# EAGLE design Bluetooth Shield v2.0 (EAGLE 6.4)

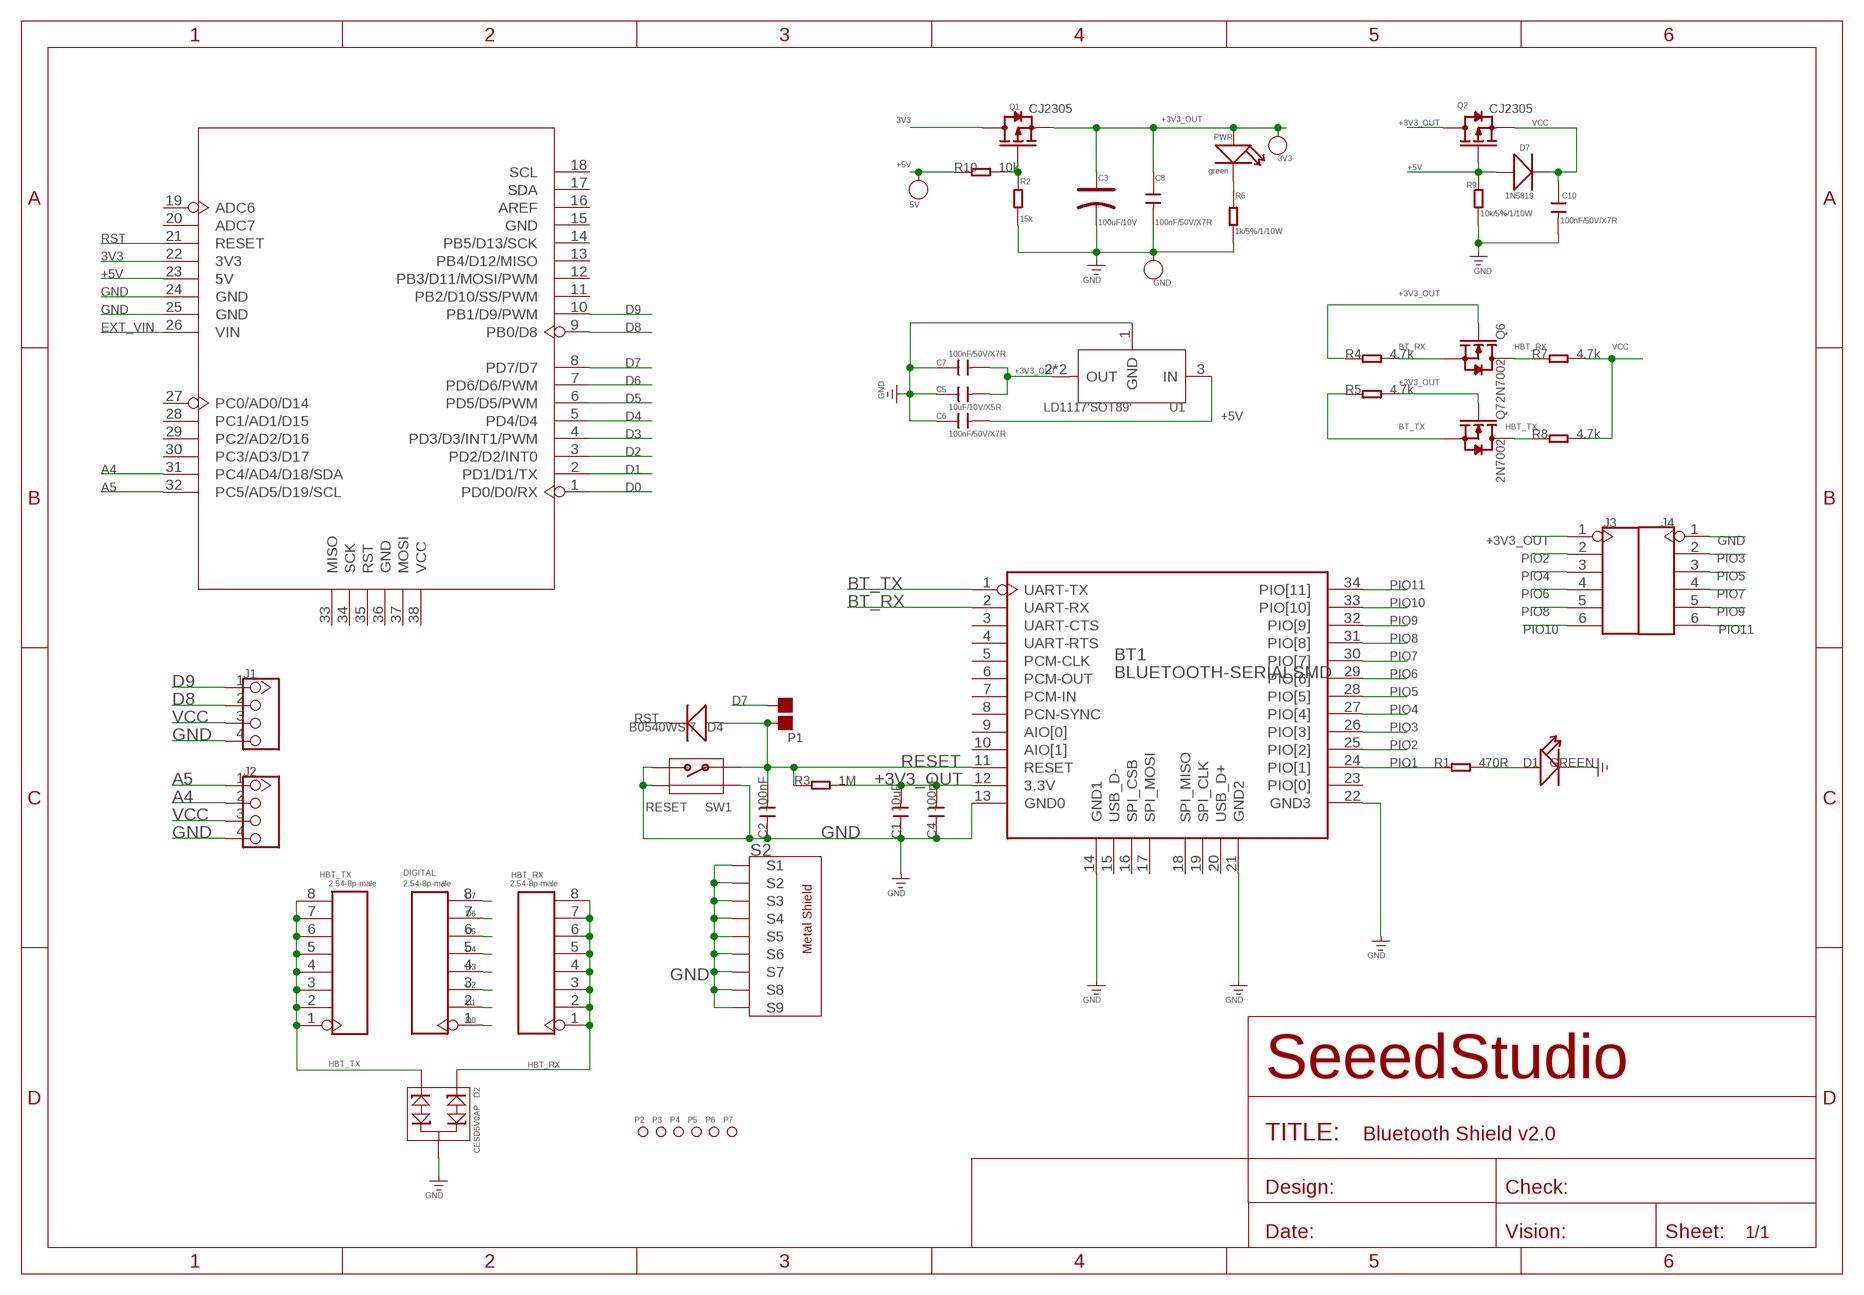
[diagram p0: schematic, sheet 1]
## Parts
3V3  PAD-TEST-POINT'4545'  [TP_4545]
5V  PAD-TEST-POINT'4545'  [TP_4545]
BT1  BLUETOOTH-SERIALSMD  [SERIAL_BLUETEETH]
C1  10uF  C-0805  [C0805]
C2  100nF  C-0603  [C0603]
C3  100uF/10V  CAP-AVX-B  [AVX-B]
C4  100nF  C-0603  [C0603]
C5  10uF/10V/X5R  C-0805  [C0805]
C6  100nF/50V/X7R  C-0603  [C0603]
C7  100nF/50V/X7R  C-0603  [C0603]
C8  100nF/50V/X7R  C-0603  [C0603]
C10  100nF/50V/X7R  C-0603  [C0603]
D1  GREEN  LED'0603'  [LED-0603]
D2  CESD5V0AP  D-ESD-PESDXL2BT  [SOT23]
D4  B0540WS-7  D'1206'  [SOD123]
D7  1N5819  D'DO-214AC'  [D2010]
DIGITAL  2.54-8p-male  HEADER-8P-2.54  [8P-2.54]
GND  GND  PAD-TEST-POINT'4545'  [TP_4545]
HBT_RX  2.54-8p-male  HEADER-8P-2.54  [8P-2.54]
HBT_TX  2.54-8p-male  HEADER-8P-2.54  [8P-2.54]
J1  TWIG-4P-2.0-2.0  [4P-2.0]
J2  TWIG-4P-2.0-2.0  [4P-2.0]
J3  HEADER-6P-65/35MIL  [6P-2.54-65/35MIL]
J4  HEADER-6P-65/35MIL  [6P-2.54-65/35MIL]
P1  PAD-JUMPER-2P  [2P-SMD-1.78X1.27]
P2  PAD-MARK'ANNULAR'  [ROUND-MARK-1.0]
P3  PAD-MARK'ANNULAR'  [ROUND-MARK-1.0]
P4  PAD-MARK'ANNULAR'  [ROUND-MARK-1.0]
P5  PAD-MARK'ANNULAR'  [ROUND-MARK-1.0]
P6  PAD-MARK'ANNULAR'  [ROUND-MARK-1.0]
P7  PAD-MARK'ANNULAR'  [ROUND-MARK-1.0]
PWR  green  LED'0603'  [LED-0603]
Q1  CJ2305  MOSFET-P'SI2323CDS/SI2305DS<BR>'  [SOT23]
Q2  CJ2305  MOSFET-P'SI2323CDS/SI2305DS<BR>'  [SOT23]
Q6  2N7002  MOSFET-N'SOT23'  [SOT23]
Q7  2N7002  MOSFET-N'SOT23'  [SOT23]
R1  470R  R-0603  [R0603]
R2  15k  R-0603  [R0603]
R3  1M  R-0603  [R0603]
R4  4.7k  R-0603  [R0603]
R5  4.7k  R-0603  [R0603]
R6  1k/5%/1/10W  R-0603  [R0603]
R7  4.7k  R-0603  [R0603]
R8  4.7k  R-0603  [R0603]
R9  10k/5%/1/10W  R-0603  [R0603]
R10  10k  R-0603  [R0603]
S2  EMI_SHIELD-FRAME_BT  [BT_SHIELD]
SW1  RESET  BUTTON-4P-REINFORCE'TS-1188E'  [4P-SMD-7X3.5X3.5H]
U1  LD1117'SOT89'  [SOT89]
U4  ARDUINO-38P'WITH/-SILK'  [ARDUINO-38P-WITH/-SILK-500519002]

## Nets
3V3: Q1.3(D) U4.22(3V3)
+3V3_OUT: 3V3.T BT1.12(3.3V) C1.2 C3.+ C4.2 C5.2 C7.2 C8.1 J3.1 PWR.+ Q1.2(S) Q2.3(D) Q6.1(G) Q7.1(G) R3.2 R4.1 R5.2 U1.2(OUT) U1.4(OUT)
+5V: 5V.T C6.2 D7.+ Q2.1(G) R9.1 R10.1 U1.3(IN) U4.23(5V)
A4: J2.2 U4.31(PC4/AD4/D18/SDA)
A5: J2.1 U4.32(PC5/AD5/D19/SCL)
BT_RX: BT1.2(UART-RX) Q6.2(S) R4.2
BT_TX: BT1.1(UART-TX) Q7.2(S) R5.1
D0: DIGITAL.1 U4.1(PD0/D0/RX)
D1: DIGITAL.2 U4.2(PD1/D1/TX)
D2: DIGITAL.3 U4.3(PD2/D2/INT0)
D3: DIGITAL.4 U4.4(PD3/D3/INT1/PWM)
D4: DIGITAL.5 U4.5(PD4/D4)
D5: DIGITAL.6 U4.6(PD5/D5/PWM)
D6: DIGITAL.7 U4.7(PD6/D6/PWM)
D7: DIGITAL.8 P1.1 U4.8(PD7/D7)
D8: J1.2 U4.9(PB0/D8)
D9: J1.1 U4.10(PB1/D9/PWM)
EXT_VIN: U4.26(VIN)
GND: BT1.13(GND0) BT1.14(GND1) BT1.21(GND2) BT1.22(GND3) C1.1 C2.1 C3.- C4.1 C5.1 C6.1 C7.1 C8.2 C10.2 D1.- D2.3 GND.T J1.4 J2.4 J4.1 R2.2 R6.1 R9.2 S2.S1 S2.S2 S2.S3 S2.S4 S2.S5 S2.S6 S2.S7 S2.S8 S2.S9 SW1.2 SW1.S1 SW1.S2 U1.1(GND) U4.24(GND) U4.25(GND)
HBT_RX: D2.1 HBT_RX.1 HBT_RX.2 HBT_RX.3 HBT_RX.4 HBT_RX.5 HBT_RX.6 HBT_RX.7 HBT_RX.8 Q6.3(D) R7.1
HBT_TX: D2.2 HBT_TX.1 HBT_TX.2 HBT_TX.3 HBT_TX.4 HBT_TX.5 HBT_TX.6 HBT_TX.7 HBT_TX.8 Q7.3(D) R8.1
N$1: Q1.1(G) R2.1 R10.2
N$5: D1.+ R1.2
N$26: PWR.- R6.2
PIO1: BT1.24(PIO[1]) R1.1
PIO2: BT1.25(PIO[2]) J3.2
PIO3: BT1.26(PIO[3]) J4.2
PIO4: BT1.27(PIO[4]) J3.3
PIO5: BT1.28(PIO[5]) J4.3
PIO6: BT1.29(PIO[6]) J3.4
PIO7: BT1.30(PIO[7]) J4.4
PIO8: BT1.31(PIO[8]) J3.5
PIO9: BT1.32(PIO[9]) J4.5
PIO10: BT1.33(PIO[10]) J3.6
PIO11: BT1.34(PIO[11]) J4.6
RESET: BT1.11(RESET) C2.2 D4.+ P1.2 R3.1 SW1.1
RST: D4.- U4.21(RESET)
VCC: C10.1 D7.- J1.3 J2.3 Q2.2(S) R7.2 R8.2
Unconnected: BT1.3(UART-CTS) BT1.4(UART-RTS) BT1.5(PCM-CLK) BT1.6(PCM-OUT) BT1.7(PCM-IN) BT1.8(PCN-SYNC) BT1.9(AIO[0]) BT1.10(AIO[1]) BT1.15(USB_D-) BT1.16(SPI_CSB) BT1.17(SPI_MOSI) BT1.18(SPI_MISO) BT1.19(SPI_CLK) BT1.20(USB_D+) BT1.23(PIO[0]) U4.11(PB2/D10/SS/PWM) U4.12(PB3/D11/MOSI/PWM) U4.13(PB4/D12/MISO) U4.14(PB5/D13/SCK) U4.15(GND) U4.16(AREF) U4.17(SDA) U4.18(SCL) U4.19(ADC6) U4.20(ADC7) U4.27(PC0/AD0/D14) U4.28(PC1/AD1/D15) U4.29(PC2/AD2/D16) U4.30(PC3/AD3/D17) U4.33(MISO) U4.34(SCK) U4.35(RST) U4.36(GND) U4.37(MOSI) U4.38(VCC)

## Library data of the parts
3V3 5V GND = Discrete:PAD-TEST-POINT; PARTNO: DNP
BT1 = Module:BLUETOOTH-SERIAL
C1 C2 C4-C8 C10 = Discrete:C*: Ceramic Capacitors
C3 = Discrete:CAP*: Electrolytic Capacitors,Tantalum Capacitors and Super Capacitors
D1 PWR = Discrete:LED*
D2 = Discrete:D-ESD-PESDXL2BT
D4 D7 = Discrete:D*
DIGITAL HBT_RX HBT_TX = Connector:HEADER-8P
J1 J2 = Connector :TWIG-4P-2.0
J3 J4 = Connector :HEADER-6P
P1 = Discrete:PAD-JUMPER-2P; PARTNO: DNP
P2-P7 = Discrete:PAD-MARK; PARTNO: DNP
Q1 Q2 = Discrete:MOSFET-P
Q6 Q7 = Discrete:MOSFET-N: IRLL014: http://www.vishay.com/docs/91319/sihll014.pdf
R1-R10 = Discrete:R*
S2 = moudle:EMI_SHIELD-FRAME
SW1 = Discrete:BUTTON-4P-REINFORCE: TS-1188E http://www.best-dz.com/?thread-374-2.html
U1 = IC:LD1117: Low Drop Fixed And Adjustable Positive Voltage Regulators http://www.datasheetcatalog.org/datasheet/SGSThomsonMicroelectronics/mXuqtqv.pdf
U4 = moudle:ARDUINO-38P

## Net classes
0 default: width 0.003 mm, drill 0.254 mm, clearance 0.152 mm

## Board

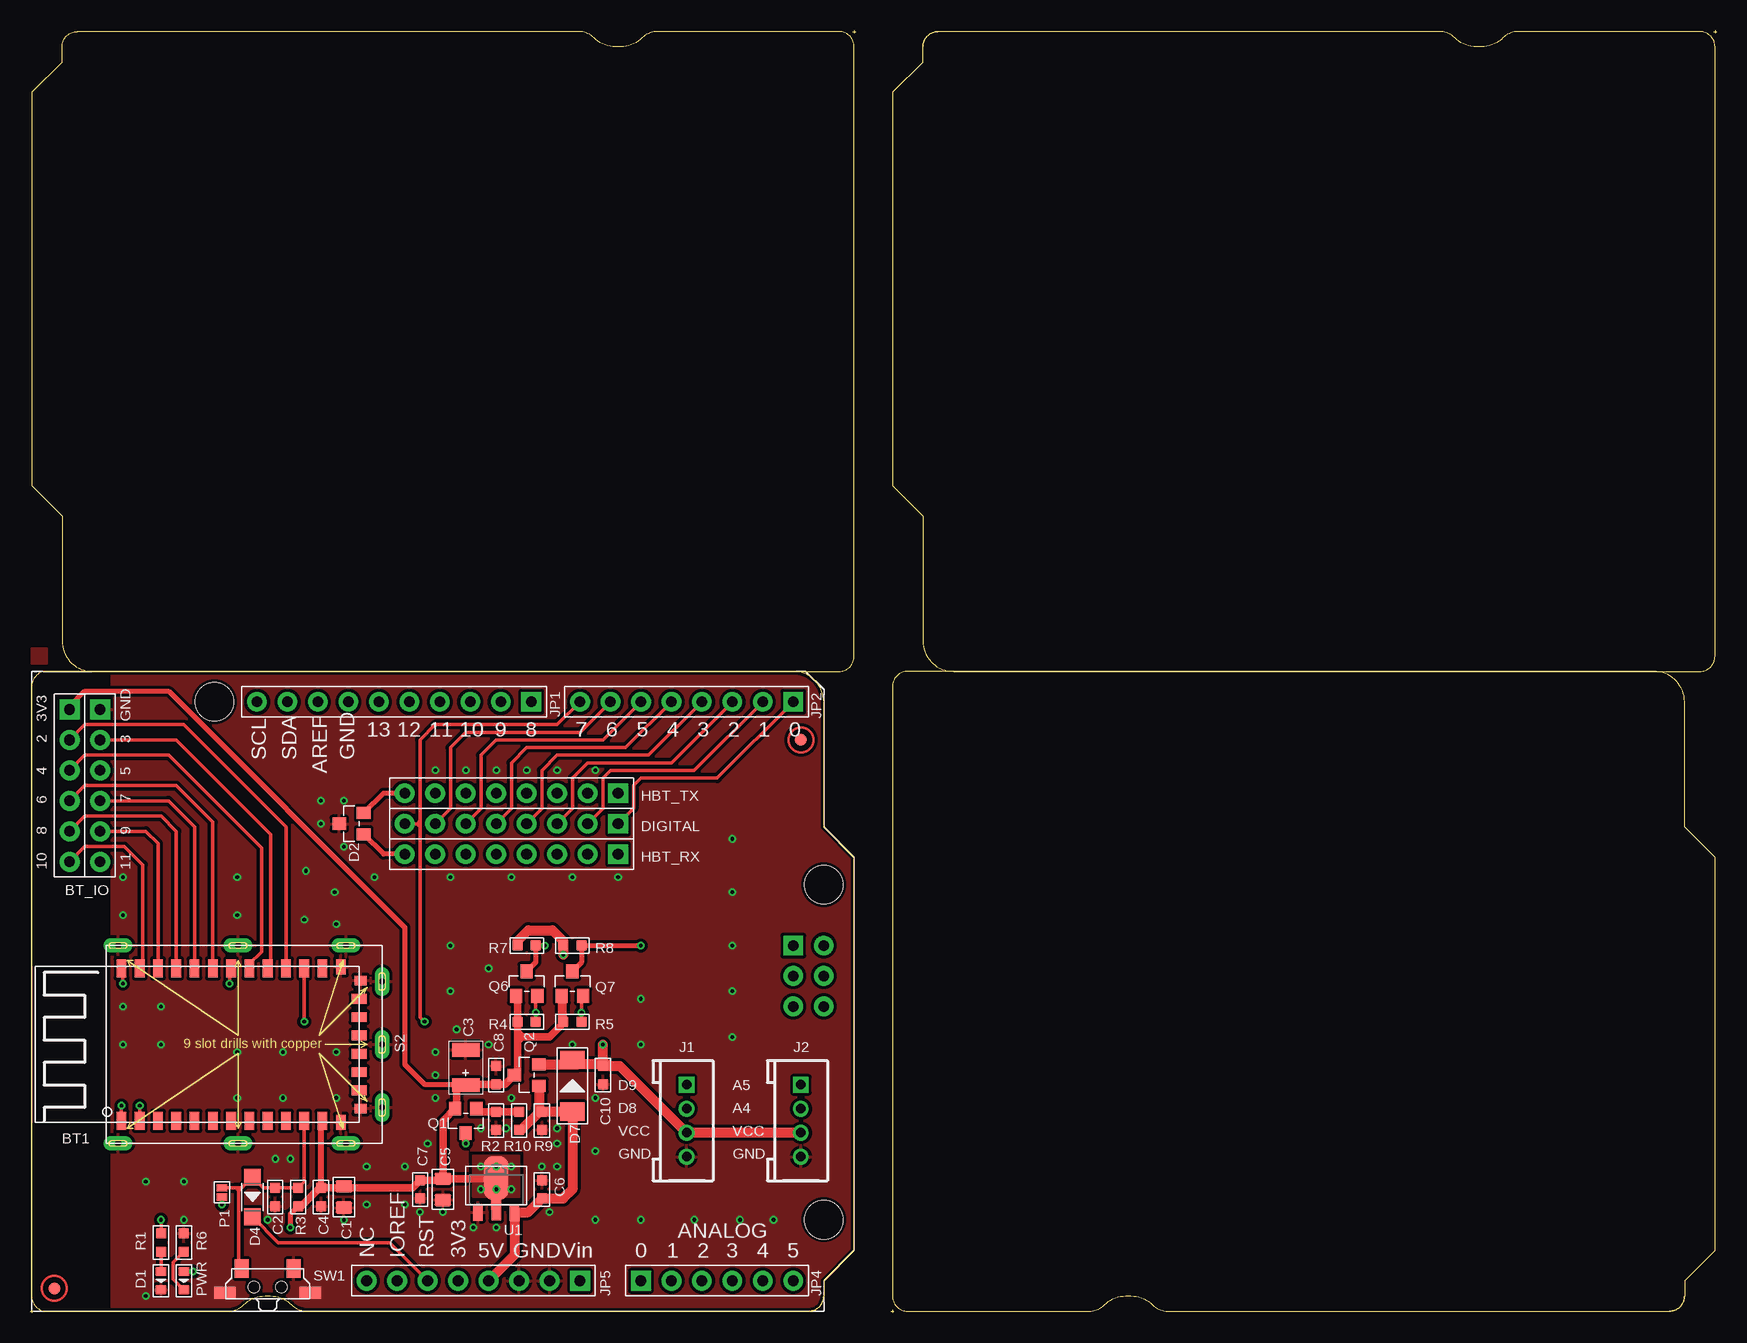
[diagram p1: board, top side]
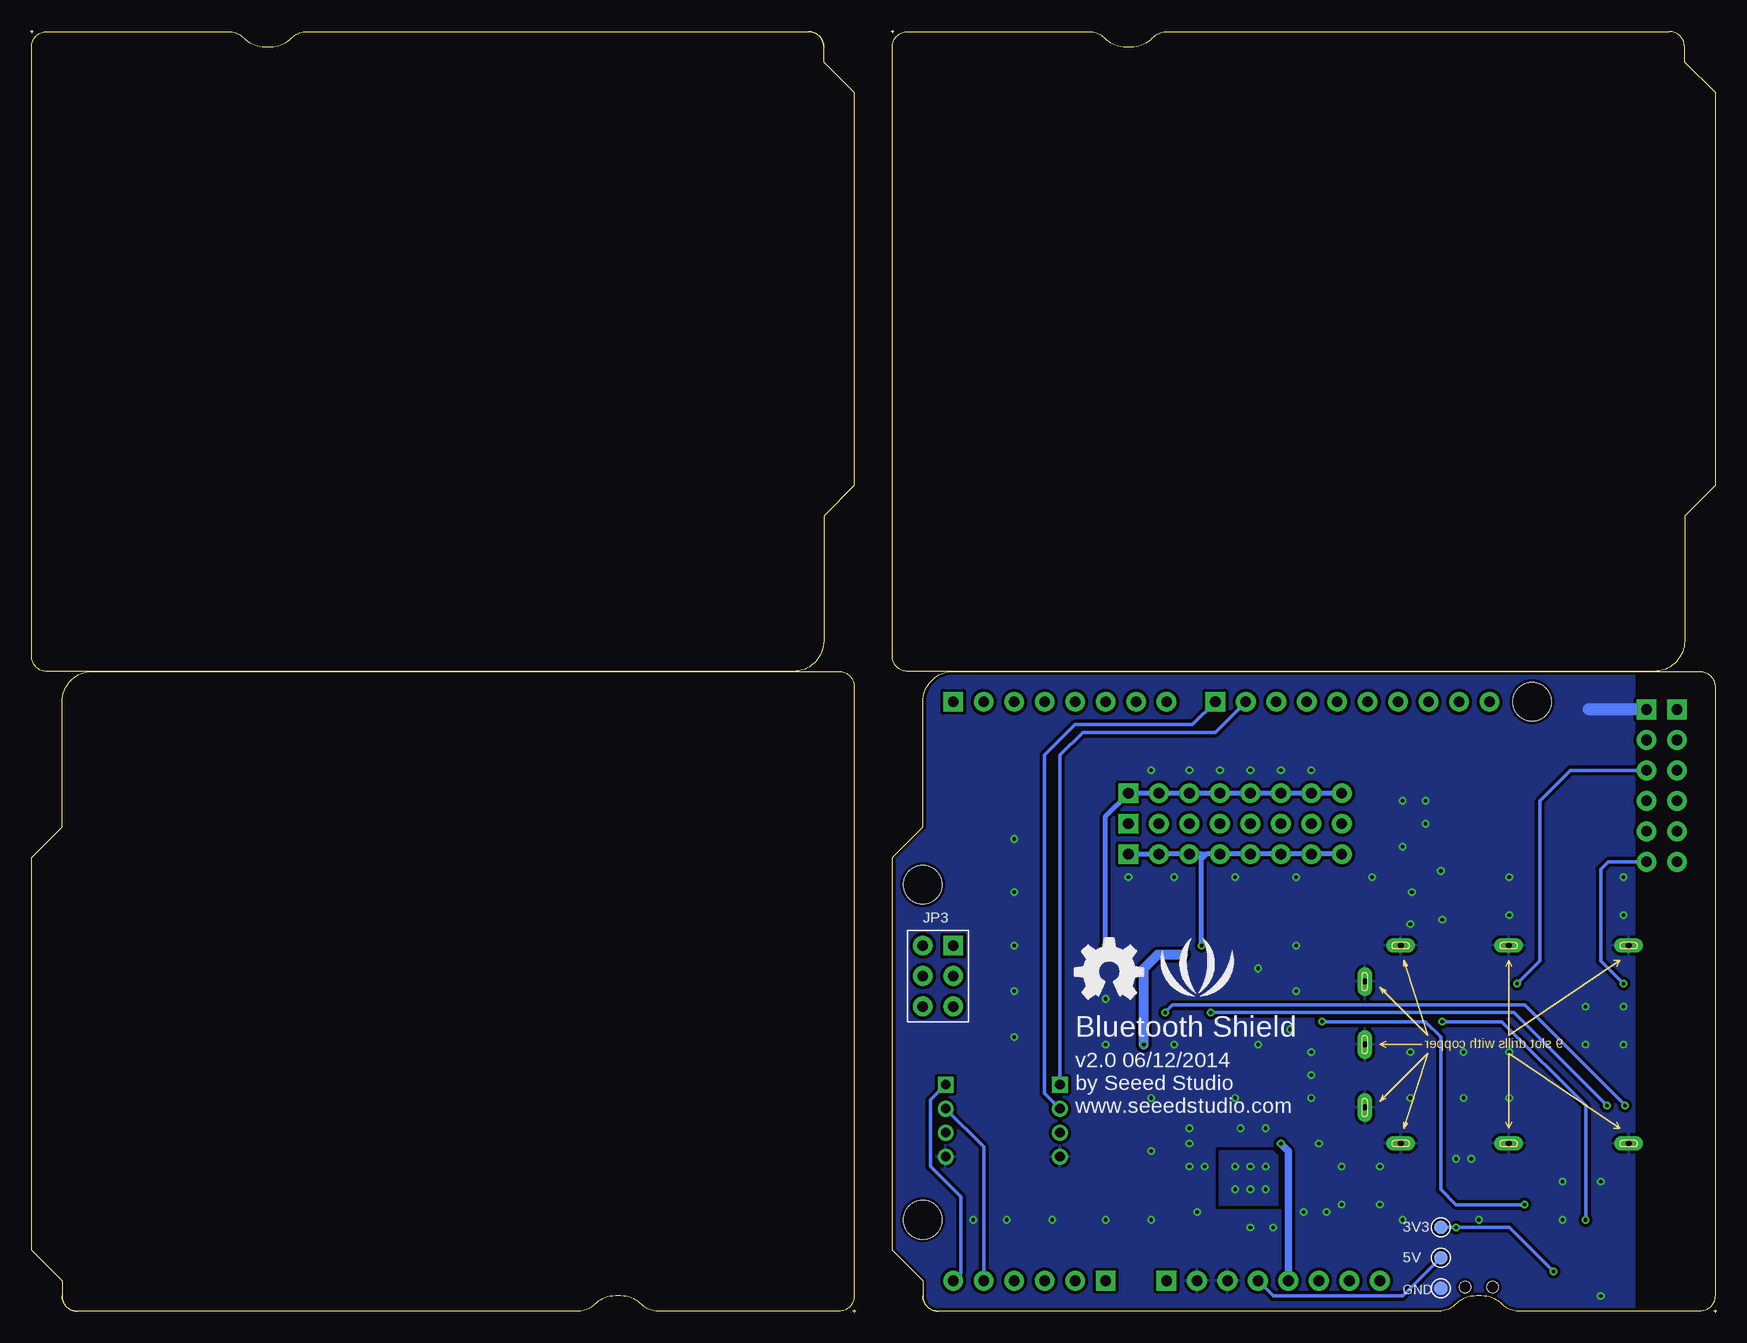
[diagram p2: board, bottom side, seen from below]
Size 140.59 x 106.93 mm. Coordinates in mm from the lower left corner, seen from the top.
Outline: 112 segments
Copper layers (1*16): Top 0.035mm / dielectric 1.5mm / Bottom 0.035mm
Design rules "default *": minimum track width 6mil, minimum drill 12mil, track to track 6mil, track to pad 6mil, pad to pad 6mil, via to via 6mil, smd to smd 0mil, copper to edge 10mil, drill to drill 10mil, minimum pad ring 10mil, minimum via ring 6mil, stop-mask expansion 2mil, vias tented up to drill 100mil, thermal gap 10mil
Holes 2.03 mm at 7.75,111.25 132.84,111.25 132.84,-4.32 7.75,-4.32
tRestrict: area 0.1,0.1 to 6.5,53.5
bRestrict: area 0.1,0.1 to 6.5,53.5

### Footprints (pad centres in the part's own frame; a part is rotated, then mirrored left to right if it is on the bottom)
TP_4545 = smd 1.143 x 1.143: T 0,0
SERIAL_BLUETEETH = smd 1.524 x 0.813: 1 -6.35,19.812; 2 -6.35,18.288; 3 -6.35,16.764; 4 -6.35,15.24; 5 -6.35,13.716; 6 -6.35,12.192; 7 -6.35,10.668; 8 -6.35,9.144; 9 -6.35,7.62; 10 -6.35,6.096; 11 -6.35,4.572; 12 -6.35,3.048; 23 6.35,3.048; 24 6.35,4.572; 25 6.35,6.096; 26 6.35,7.62; 27 6.35,9.144; 28 6.35,10.668; 29 6.35,12.192; 30 6.35,13.716; 31 6.35,15.24; 32 6.35,16.764; 33 6.35,18.288; 34 6.35,19.812 | smd 1.27 x 0.813: 13 -6.477,1.524; 22 6.477,1.524 | smd 0.813 x 1.016: 14 -5.334,-0.127; 21 5.334,-0.127 | smd 0.813 x 1.27: 15 -3.81,0; 16 -2.286,0; 17 -0.762,0; 18 0.762,0; 19 2.286,0; 20 3.81,0
C0805 = smd 1.016 x 1.397: 1 -0.889,0; 2 0.889,0
C0603 = smd 0.889 x 0.889: 1 -0.762,0; 2 0.762,0
AVX-B = smd 1.143 x 2.286: + -1.46,0; - 1.46,0
LED-0603 = smd 0.762 x 0.889: + -0.762,0; - 0.762,0
SOT23 = smd 1.016 x 1.143: 1 -0.889,-1.016; 2 0.889,-1.016; 3 0,1.016
SOD123 = smd 1.397 x 1.397: + -1.651,0; - 1.651,0
D2010 = smd 1.524 x 2.032: + -2.159,0; - 2.159,0
8P-2.54 = drill 0.889 pad 1.651 square: 1 0,8.89 | drill 0.889 pad 1.651: 2 0,6.35; 3 0,3.81; 4 0,1.27; 5 0,-1.27; 6 0,-3.81; 7 0,-6.35; 8 0,-8.89
4P-2.0 = drill 0.8 pad 1.27 square: 1 -3,0 | drill 0.8 pad 1.27: 2 -1,0; 3 1,0; 4 3,0
6P-2.54-65/35MIL = drill 0.889 pad 1.651 square: 1 0,6.35 | drill 0.889 pad 1.651: 2 0,3.81; 3 0,1.27; 4 0,-1.27; 5 0,-3.81; 6 0,-6.35
2P-SMD-1.78X1.27 = smd 0.889 x 0.61: 1 0,0.381; 2 0,-0.381
ROUND-MARK-1.0 = smd 1.016 x 1.016: P$1 0,0
R0603 = smd 0.889 x 0.889: 1 -0.762,0; 2 0.762,0
BT_SHIELD = drill 0.5 pad 1.2 long: S1 0,5.25; S2 0,0; S3 0,-5.25; S4 3,-8.25; S5 12,-8.25; S6 22,-8.25; S7 22,8.25; S8 12,8.25; S9 3,8.25
4P-SMD-7X3.5X3.5H = smd 1.143 x 1.524: 1 -2.159,1.524; 2 2.159,1.524 | smd 1.778 x 1.016: S1 -3.556,-0.508; S2 3.556,-0.508 | hole 0.95: -1.15,0; 1.15,0
SOT89 = smd 0.8 x 1.4: 1 -1.524,-1.905; 3 1.524,-1.905 | smd 0.8 x 1.9: 2 0,-1.651 | smd 2.032 x 3.65: 4 0,0.94
ARDUINO-38P-WITH/-SILK-500519002 = drill 0.889 pad 1.651 square: 1 63.5,50.8; 9 41.656,50.8; 26 45.72,2.54; 27 50.8,2.54; 33 63.5,30.48 | drill 0.889 pad 1.651: 2 60.96,50.8; 3 58.42,50.8; 4 55.88,50.8; 5 53.34,50.8; 6 50.8,50.8; 7 48.26,50.8; 8 45.72,50.8; 10 39.116,50.8; 11 36.576,50.8; 12 34.036,50.8; 13 31.496,50.8; 14 28.956,50.8; 15 26.416,50.8; 16 23.876,50.8; 17 21.336,50.8; 18 18.796,50.8; 19 27.94,2.54; 20 30.48,2.54; 21 33.02,2.54; 22 35.56,2.54; 23 38.1,2.54; 24 40.64,2.54; 25 43.18,2.54; 28 53.34,2.54; 29 55.88,2.54; 30 58.42,2.54; 31 60.96,2.54; 32 63.5,2.54; 34 63.5,27.94; 35 63.5,25.4; 36 66.04,25.4; 37 66.04,27.94; 38 66.04,30.48 | hole 3.2: 15.24,50.8; 66.04,35.56; 66.04,7.62

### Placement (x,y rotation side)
3V3  22.99,7.11 0 bottom
5V  22.99,4.57 0 bottom
BT1  27.43,22.35 90 top
C1  26.16,9.65 90 top
C2  20.45,9.65 90 top
C3  36.32,20.45 90 top
C4  24.26,9.65 90 top
C5  34.42,10.29 90 top
C6  42.67,10.29 270 top
C7  32.51,10.29 90 top
C8  38.86,19.81 90 top
C10  47.75,19.81 270 top
D1  10.92,2.67 270 top
D2  26.8,40.77 90 top
D4  18.54,9.65 270 top
D7  45.21,18.92 90 top
DIGITAL  40.13,40.77 270 top
GND  22.99,2.03 0 bottom
HBT_RX  40.13,38.23 270 top
HBT_TX  40.13,43.31 270 top
J1  54.74,16 270 top
J2  64.26,16 270 top
J3  3.3,43.94 0 top
J4  5.84,43.94 0 top
P1  16,10.03 180 top
P2  2.03,2.03 0 top
P3  64.26,47.75 0 top
P4  not placed on the board
P5  not placed on the board
P6  not placed on the board
P7  not placed on the board
PWR  12.83,2.67 270 top
Q1  36.32,16 180 top
Q2  41.4,19.81 90 top
Q6  41.4,27.43 0 top
Q7  45.21,27.43 0 top
R1  10.92,5.84 270 top
R2  38.86,16 270 top
R3  22.35,9.65 270 top
R4  41.4,24.26 0 top
R5  45.21,24.26 180 top
R6  12.83,5.84 270 top
R7  41.4,30.61 180 top
R8  45.21,30.61 180 top
R9  42.67,16 270 top
R10  40.77,16 90 top
S2  29.34,22.35 180 top
SW1  19.81,2.16 0 top
U1  38.86,10.29 0 top
U4  0.13,0.13 0 top
U$26  [LOGO_SILK]  43.31,28.07 0 bottom
U$28  [OSHW_FILLX200_NOTEXT]  53.47,26.16 0 bottom

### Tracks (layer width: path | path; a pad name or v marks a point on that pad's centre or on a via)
3V3  (via drill 0.3 pad 0.64)
  Top 0.61: v36.32,14.1 Q1.3
  Bottom 0.61: U4.22 35.69,13.46 v36.32,14.1
+3V3_OUT  (via drill 0.3 pad 0.64)
  Top 0.305: 38.81,11.18 38.81,10.34 v38.86,10.29 | PWR.+ v13.59,3.43
  Top 0.406: 24.26,15.88 BT1.12 | v21.72,7.11 21.72,8.26 R3.2 | 36.26,19.05 32.89,19.05 31.24,20.7 31.24,32.13 11.56,51.82 4.57,51.82 3.3,50.55 J3.1
  Top 0.508: C4.2 24.26,15.88
  Top 0.61: C5.2 34.29,11.05 C7.2 31.88,10.41 26.29,10.41 C1.2 26.04,10.41 C4.2 24.13,10.41 22.61,8.89 R3.2 | C5.2 38.81,11.18 U1.4 | Q6.1 40.64,26.29 R4.1 40.64,23.37 | R5.2 44.45,26.29 Q7.1 44.32,24 43.31,22.99 41.02,22.99 | 40.64,22.99 40.64,22.61 | 40.64,22.61 40.64,20.07 Q2.3 39.62,19.05 C8.1 36.26,19.05 | 41.02,22.99 40.64,22.99 | C5.2 34.42,16 Q1.2 35.56,17.14 35.56,18.92 35.62,18.99 C3.+ 36.26,19.05 | 41.02,22.99 40.64,23.37 | 41.02,22.99 40.64,22.61 | 40.64,22.99 40.64,23.37 | 35.75,19.05 36.26,19.05
  Top 0.813: U1.2 v38.86,10.29 U1.4
  Bottom 0.305: 3V3.T v21.72,7.11 17.27,7.11 v13.59,3.43
  other vias: 37.59,12.19 38.86,12.19 40.13,12.19 40.13,10.29 37.59,10.29
  pour Bottom (isolate 0.508): 36.32,13.46 41.4,13.46 41.4,9.02 36.32,9.02
  pour Top (isolate 0.254, no thermals): 36.96,13.08 40.77,13.08 40.77,9.65 36.96,9.65
+5V
  Top 0.813: R9.1 D7.+ 45.21,10.29 44.45,9.53 C6.2 41.53,8.38 U1.3 40.39,4.83 U4.23 | Q2.1 42.42,17.02 R9.1 | R10.1 40.96,15.24 42.48,16.76 R9.1
  Bottom 0.305: U4.23 36.96,1.4 26.16,1.4 5V.T
A4
  Bottom 0.305: U4.31 61.09,13.83 J2.2
A5
  Bottom 0.305: J2.1 65.53,17.73 65.53,12.19 62.99,9.65 62.99,3.3 U4.32
BT_RX  (via drill 0.3 pad 0.64)
  Top 0.305: R4.2 v42.16,25.02 42.16,26.29 Q6.2 | v9.14,17.27 BT1.2
  Bottom 0.305: v42.16,25.02 16.89,25.02 v9.14,17.27
BT_TX  (via drill 0.3 pad 0.64)
  Top 0.305: R5.1 v45.97,25.02 45.97,26.29 Q7.2 | v7.62,17.27 BT1.1
  Bottom 0.305: v45.97,25.02 45.34,25.65 16,25.65 v7.62,17.27
D0
  Top 0.305: U4.1 57.28,44.58 50.93,44.58 50.29,43.94 50.29,42.04 DIGITAL.1
D1
  Top 0.305: U4.2 55.37,45.21 48.39,45.21 47.75,44.58 47.75,42.04 DIGITAL.2
D2
  Top 0.305: U4.3 53.47,45.85 46.48,45.85 45.21,44.58 45.21,42.04 DIGITAL.3
D3
  Top 0.305: U4.4 51.56,46.48 43.94,46.48 42.67,45.21 42.67,42.04 DIGITAL.4
D4
  Top 0.305: U4.5 49.66,47.12 41.4,47.12 40.13,45.85 40.13,42.04 DIGITAL.5
D5
  Top 0.305: U4.6 47.75,47.75 38.86,47.75 37.59,46.48 37.59,42.04 DIGITAL.6
D6
  Top 0.305: U4.7 45.85,48.39 36.32,48.39 35.05,47.12 35.05,42.04 DIGITAL.7
D7  (via drill 0.3 pad 0.64)
  Top 0.305: U4.8 43.94,49.02 33.78,49.02 32.51,47.75 32.51,41.02 | P1.1 v16,9.02 | 32.51,40.77 32.51,40.51 | DIGITAL.8 32.26,40.77 | 32.26,40.77 32.51,40.77 | 32.26,40.77 32.51,41.02 | 32.26,40.77 32.51,40.51 | 32.51,40.77 32.51,41.02 | 32.51,40.51 32.51,24.64 v32.89,24.26
  Bottom 0.305: v32.89,24.26 24.26,24.26 22.99,22.99 22.99,10.29 21.72,9.02 v16,9.02
D8
  Bottom 0.305: U4.9 43.69,49.02 53.47,49.02 56.01,46.48 56.01,18.27 J1.2
D9
  Bottom 0.305: J1.1 54.74,46.48 52.83,48.39 41.78,48.39 U4.10
GND  (via drill 0.3 pad 0.64)
  Bottom 1.016: J4.1 10.67,50.29
  other vias: 26.16,7.75 12.83,7.75 19.81,7.75 32.51,8.38 36.96,7.11 42.67,12.19 43.94,15.37 43.94,14.1 39.69,15.37 35.56,23.62 38.23,28.7 38.23,22.35 35.05,26.8 47.12,17.91 47.12,13.46 45.21,36.32 45.21,22.35 49.02,36.32 40.13,36.32 35.05,36.32 47.12,45.21 43.94,45.21 41.4,45.21 38.86,45.21 36.32,45.21 33.78,45.21 31.24,9.02 28.07,9.02 33.78,21.72 40.13,17.91 33.78,19.81 50.93,26.16 50.93,22.35 28.07,12.19 31.24,12.19 33.78,17.91 24.26,40.77 22.99,36.83 26.16,38.86 24.26,42.67 26.16,42.67 43.94,12.19 47.12,7.75 33.15,14.1 43.31,8.38 25.53,17.91 25.53,21.72 21.08,21.72 21.08,17.91 17.27,21.72 17.27,17.91 7.75,25.53 10.92,25.53 10.92,22.35 7.75,22.35 58.55,35.05 58.55,30.61 58.55,26.8 58.55,22.99 12.83,10.92 22.86,32.77 28.7,36.32 17.27,33.15 17.27,36.32 7.75,36.32 7.75,33.15 50.93,7.75 55.37,7.75 58.55,39.5 20.45,12.83 21.72,12.83 35.05,30.61 34.42,8.38 9.65,1.4 9.65,10.92 61.98,7.75 59.18,7.75 38.86,7.11 25.4,35.05 25.53,32.39 37.59,15.37
  pour Top (isolate 0.254): 0.13,55.37 1.4,55.37 1.4,54.1 0.13,54.1
  pour Top (isolate 0.254, rank 6): 0.13,53.47 68.71,53.47 68.71,0.13 0.13,0.13
  pour Bottom (isolate 0.254, rank 6): 0.13,53.47 68.71,53.47 68.71,0.13 0.13,0.13
HBT_RX  (via drill 0.3 pad 0.64)
  Top 0.406: Q6.3 42.16,29.21 R7.1 v42.93,30.61 | HBT_RX.8 29.46,38.23 D2.1
  Bottom 0.406: HBT_RX.8 HBT_RX.7 HBT_RX.6 HBT_RX.5 HBT_RX.4 42.55,38.23 | 42.93,38.23 43.31,38.23 | 43.31,38.23 HBT_RX.3 HBT_RX.2 HBT_RX.1 | v42.93,30.61 42.93,37.85 | 42.93,37.85 42.93,38.23 | 42.55,38.23 42.93,37.85 | 42.93,37.85 43.31,38.23 | 42.93,38.23 42.55,38.23
HBT_TX  (via drill 0.3 pad 0.64)
  Top 0.406: Q7.3 45.97,29.21 R8.1 v50.93,30.61 | HBT_TX.8 29.46,43.31 D2.2
  Bottom 0.406: HBT_TX.8 HBT_TX.7 HBT_TX.6 HBT_TX.5 HBT_TX.4 HBT_TX.3 HBT_TX.2 HBT_TX.1 50.93,41.4 v50.93,30.61
N$1
  Top 0.61: R10.2 R2.1 37.47,16.76 Q1.1
N$5
  Top 0.305: D1.+ R1.2
N$26
  Top 0.305: R6.2 11.94,4.19 11.94,2.79 PWR.-
PIO1  (via drill 0.3 pad 0.64)
  Top 0.305: R1.1 v10.92,7.75 | v22.86,24.26 BT1.24
  Bottom 0.305: v22.86,24.26 17.91,24.26 10.92,17.27 v10.92,7.75
PIO2
  Top 0.305: BT1.25 21.34,40.51 12.83,49.02 4.57,49.02 J3.2
PIO3
  Top 0.305: J4.2 12.19,47.75 20.07,39.88 20.07,29.34 19.81,29.08 BT1.26
PIO4
  Top 0.305: BT1.27 18.29,29.08 19.3,30.1 19.3,38.73 11.56,46.48 4.57,46.48 J3.3
PIO5  (via drill 0.3 pad 0.64)
  Top 0.305: v16.64,27.43 16.64,28.57 BT1.28
  Bottom 0.305: v16.64,27.43 14.73,29.34 14.73,42.67 12.19,45.21 J4.3
PIO6
  Top 0.305: BT1.29 15.24,40.89 12.19,43.94 4.57,43.94 J3.4
PIO7
  Top 0.305: BT1.30 13.72,40.51 11.56,42.67 J4.4
PIO8
  Top 0.305: BT1.31 12.19,40.13 10.92,41.4 4.57,41.4 J3.5
PIO9
  Top 0.305: BT1.32 10.67,39.12 9.65,40.13 J4.5
PIO10
  Top 0.305: BT1.33 9.4,28.7 9.4,37.34 7.87,38.86 4.57,38.86 J3.6
PIO11  (via drill 0.3 pad 0.64)
  Top 0.305: v7.75,27.43 7.75,28.57 BT1.34
  Bottom 0.305: v7.75,27.43 9.65,29.34 9.65,36.96 9.02,37.59 J4.6
RESET
  Top 0.305: BT1.11 22.86,10.92 R3.1 C2.2 19.43,10.41 D4.+ 17.65,10.41 | P1.2 17.14,10.41 | 17.4,10.41 17.65,10.41 | 17.4,10.41 17.4,10.16 | 17.4,10.16 17.4,3.94 SW1.1 | 17.65,10.41 17.4,10.16 | 17.4,10.16 17.14,10.41 | 17.14,10.41 17.4,10.41
RST
  Top 0.305: U4.21 29.97,5.84 20.7,5.84 D4.- 18.54,7.87
VCC  (via drill 0.3 pad 0.64)
  Top 0.813: J2.3 J1.3 49.16,20.57 48.26,20.57 | C10.1 48.26,20.57 | Q2.2 45.59,20.7 | 47.62,20.7 48.13,20.7 48.26,20.57 | C10.1 47.62,20.7 | 47.62,20.7 45.59,20.7 | 45.59,20.7 D7.- | C10.1 v47.75,22.35 | R7.2 40.64,30.99 41.53,31.88 43.56,31.88 44.45,30.99 R8.2 v44.45,29.84
  Bottom 0.813: v47.75,22.35 47.75,28.7 46.61,29.84 v44.45,29.84

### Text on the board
tPlace: 3V3 | GND | 2 | 3 | 4 | 5 | 6 | 7 | 8 | 9 | 10 | 11 | BT_IO | D9 | A5 | D8 | A4 | VCC | VCC | GND | GND
bPlace: Bluetooth Shield | v2.0 06/12/2014 | by Seeed Studio | www.seeedstudio.com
